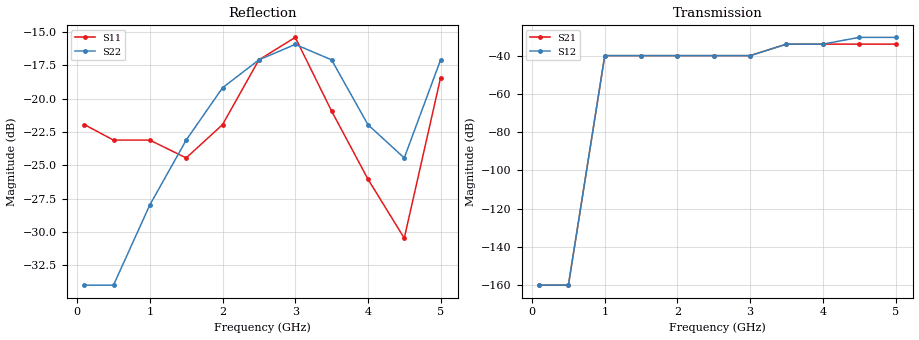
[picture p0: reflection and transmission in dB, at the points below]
!  MGS-71018 S PARAMETERS
!  "off" port  LAST UPDATED 07-22-92
# ghz s ma r 50
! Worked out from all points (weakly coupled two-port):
!   11 points, 100 MHz to 5 GHz, reference 50 ohm
!   highest |S21| = -33.98 dB at 3.5 GHz (marker M1); lowest = -40.0 dB at 1 GHz (marker M2)
!   lowest |S11| = -30.5 dB at 4.5 GHz (marker M3), VSWR 1.06, Z = 49.9 + j3 ohm
!   |S11| at or under -10 dB: start of sweep to end of sweep
!   |S22| runs from -34.0 to -15.9 dB; largest |S21 - S12| = 0.01
0.1  0.08 -18.0  0 -45.0  0 -101.0  0.02 -154.0
0.5  0.07 -62.0  0 6.0  0 -7.0  0.02 -115.0
1  0.07 -56.0  0.01 90.0  0.01 88.0  0.04 -43.0
1.5  0.06 -13.0  0.01 178.0  0.01 180.0  0.07 0.0
2  0.08 0.0  0.01 -77.0  0.01 -80.0  0.11 26.0
2.5  0.14 3.0  0.01 16.0  0.01 22.0  0.14 51.0
3  0.17 5.0  0.01 140.0  0.01 142.0  0.16 70.0
3.5  0.09 -14.0  0.02 -130.0  0.02 -132.0  0.14 90.0
4  0.05 -91.0  0.02 -26.0  0.02 -21.0  0.08 113.0
4.5  0.03 90.0  0.02 83.0  0.03 82.0  0.06 -37.0
5  0.12 102.0  0.02 -173.0  0.03 -174.0  0.14 -21.0
